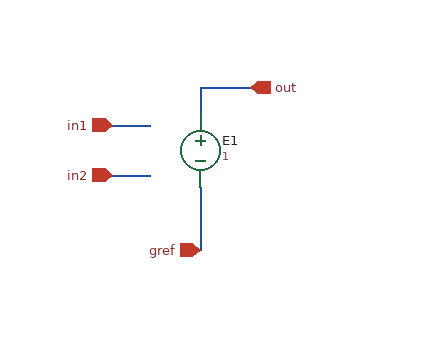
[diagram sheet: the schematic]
v {xschem version=3.4.8RC file_version=1.3}
G {}
K {}
V {}
S {}
F {}
E {}
N -70 -20 -40 -20 {lab=in1}
N -70 20 -40 20 {lab=in2}
N 0 -50 40 -50 {lab=out}
N 0 -50 0 -30 {lab=out}
N -0 30 -0 80 {lab=gref}
C {vcvs.sym} 0 0 0 0 {name=E1 value=1}
C {ipin.sym} -70 -20 0 0 {name=p1 lab=in1}
C {ipin.sym} -70 20 0 0 {name=p2 lab=in2}
C {iopin.sym} 0 80 0 0 {name=p3 lab=gref}
C {opin.sym} 40 -50 0 0 {name=p4 lab=out}
